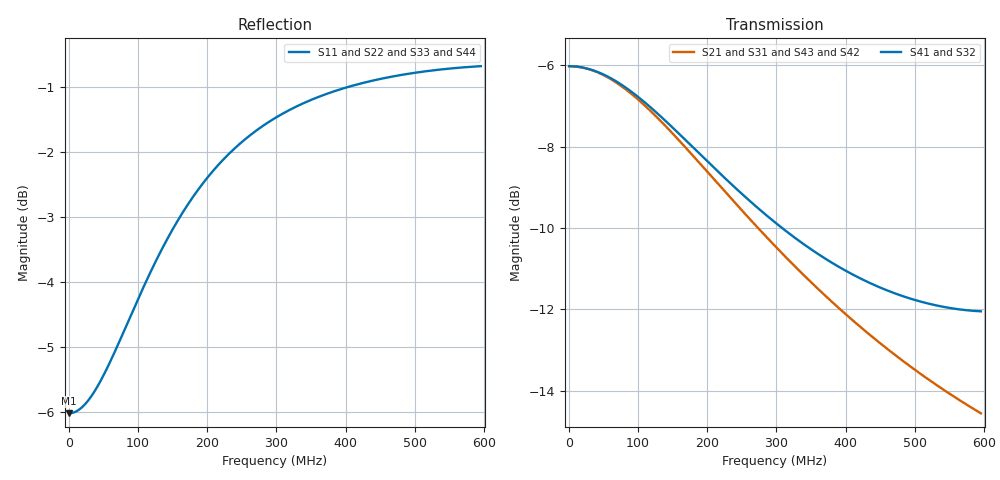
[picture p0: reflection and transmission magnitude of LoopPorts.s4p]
! Generated by circuitRF - EM: openEMS
! circuitRF-EM setup: LoopPorts CoSim
! circuitRF-EM layout: LoopPorts.c3d
! circuitRF-EM written: 2026-10-18 19:30:23Z
! circuitRF-EM geometry: 8e3466a0e8c13e94
! circuitRF-EM mesh: 1773110ca9d2a47e
! circuitRF-EM ports: f12d3ae1419e14a2
! circuitRF-EM model: openEMS 0.37.0 (v0.37.0, CSXCAD v0.7.0)
! circuitRF-EM port 1: 'port/1' from 'bottomLeft' to 'bottomRight', lumped, 50 Ohm
! circuitRF-EM port 2: 'port/2' from 'leftLower' to 'leftUpper', lumped, 50 Ohm
! circuitRF-EM port 3: 'port/3' from 'rightLower' to 'rightUpper', lumped, 50 Ohm
! circuitRF-EM port 4: 'port/4' from 'topLeft' to 'topRight', lumped, 50 Ohm
! circuitRF-EM 3D grid: 154 x 122 x 162 = 3043656 cells; smallest cell 1.6667 mm on y, set by 'OpenEms.GridLines' given line at y = -28.3333 mm
! circuitRF-EM 3D openEMS run port 1: dt 3.38654E-12 s (estimate 3.378E-12 s), 5795 steps, port signals 56.6 dB and energy 34.1 dB against 40 dB, stopped by circuitRF on the ports' decay, converged
! circuitRF-EM 3D openEMS run port 2: dt 3.38654E-12 s (estimate 3.378E-12 s), 5795 steps, port signals 56.7 dB and energy 32.7 dB against 40 dB, stopped by circuitRF on the ports' decay, converged
! circuitRF-EM 3D openEMS run port 3: dt 3.38654E-12 s (estimate 3.378E-12 s), 5795 steps, port signals 56.7 dB and energy 31.9 dB against 40 dB, stopped by circuitRF on the ports' decay, converged
! circuitRF-EM 3D openEMS run port 4: dt 3.38654E-12 s (estimate 3.378E-12 s), 5734 steps, port signals 54.2 dB and energy 34.7 dB against 40 dB, stopped by circuitRF on the ports' decay, converged
! circuitRF-EM 3D dielectric loss fitted at: 0.298 GHz
! circuitRF-EM 3D perfect conductors: bottomLeft, topLeft, bottomRight, topRight, leftLower, leftUpper, rightLower, rightUpper
! circuitRF-EM 3D operating temperature: 20 C
! circuitRF-EM 3D port fields: 'LoopPorts CoSim.openems.fields' stamp 20261018T193019Z-551edf6a
! circuitRF-EM: re-running the EM setup rewrites this file. If circuitRF reports it as stale, the layout's cross-section changed after this file was written.
# MHz S RI R 50
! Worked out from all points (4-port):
!   497 points, 400 kHz to 595.6 MHz, reference 50 ohm
!   strongest paths, dB at 400 kHz, 149.2 MHz, 298 MHz, 446.8 MHz, 595.6 MHz:
!     S41: -6.0, -7.5, -9.9, -11.4, -12.0
!     S32: -6.0, -7.5, -9.9, -11.5, -12.1
!     S21: -6.0, -7.7, -10.4, -12.8, -14.6
!     S31: -6.0, -7.7, -10.4, -12.8, -14.6
!     S43: -6.0, -7.7, -10.4, -12.8, -14.6
!     S42: -6.0, -7.7, -10.4, -12.8, -14.6
!   lowest |S11| = -6.0 dB at 400 kHz (marker M1), VSWR 3.00, Z = 150 + j0.327 ohm
!   |S11| at or under -10 dB: nowhere
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0.4  0.5 0.000818  0.5 -0.000962  -0.5 0.000962  0.5 -0.000994
     0.5 -0.000962  0.5 0.000821  0.5 -0.000992  -0.5 0.000962
     -0.5 0.000962  0.5 -0.000992  0.5 0.000821  0.5 -0.000962
     0.5 -0.000994  -0.5 0.000962  0.5 -0.000962  0.5 0.000818
42.4  0.5189 0.083  0.481 -0.0982  -0.481 0.0982  0.4809 -0.1017
      0.481 -0.0982  0.5189 0.0833  0.4809 -0.1014  -0.481 0.0982
      -0.481 0.0982  0.4809 -0.1014  0.5189 0.0833  0.481 -0.0982
      0.4809 -0.1017  -0.481 0.0982  0.481 -0.0982  0.5189 0.083
92.8  0.5794 0.1556  0.4201 -0.1889  -0.4201 0.1889  0.4198 -0.1965
      0.4201 -0.1889  0.5793 0.1562  0.4199 -0.196  -0.4201 0.1889
      -0.4201 0.1889  0.4199 -0.196  0.5794 0.1562  0.4201 -0.1889
      0.4198 -0.1965  -0.4201 0.1889  0.4201 -0.1889  0.5794 0.1556
181.6  0.7105 0.1926  0.2872 -0.2583  -0.2872 0.2583  0.2861 -0.2735
       0.2872 -0.2583  0.7104 0.1938  0.2864 -0.2726  -0.2872 0.2583
       -0.2872 0.2583  0.2863 -0.2726  0.7105 0.1938  0.2872 -0.2583
       0.2861 -0.2735  -0.2872 0.2583  0.2872 -0.2583  0.7106 0.1926
265.6  0.8046 0.1621  0.1904 -0.2592  -0.1904 0.2592  0.1879 -0.2823
       0.1904 -0.2592  0.8045 0.164  0.1883 -0.281  -0.1904 0.2592
       -0.1904 0.2592  0.1883 -0.281  0.8045 0.164  0.1904 -0.2592
       0.1879 -0.2823  -0.1904 0.2592  0.1904 -0.2592  0.8046 0.1621
356.8  0.8673 0.1054  0.1231 -0.238  -0.1231 0.238  0.1182 -0.2705
       0.1231 -0.238  0.8672 0.1078  0.1187 -0.2691  -0.1231 0.238
       -0.1231 0.238  0.1187 -0.269  0.8672 0.1078  0.1231 -0.238
       0.1182 -0.2705  -0.1231 0.238  0.1231 -0.238  0.8673 0.1053
595.6  0.9227 -0.0555  0.0435 -0.1821  -0.0435 0.1821  0.024 -0.2488
       0.0435 -0.1821  0.9214 -0.052  0.0234 -0.2475  -0.0435 0.1821
       -0.0435 0.1821  0.0234 -0.2474  0.9214 -0.0521  0.0435 -0.1821
       0.024 -0.2487  -0.0435 0.182  0.0435 -0.1821  0.9227 -0.0556
